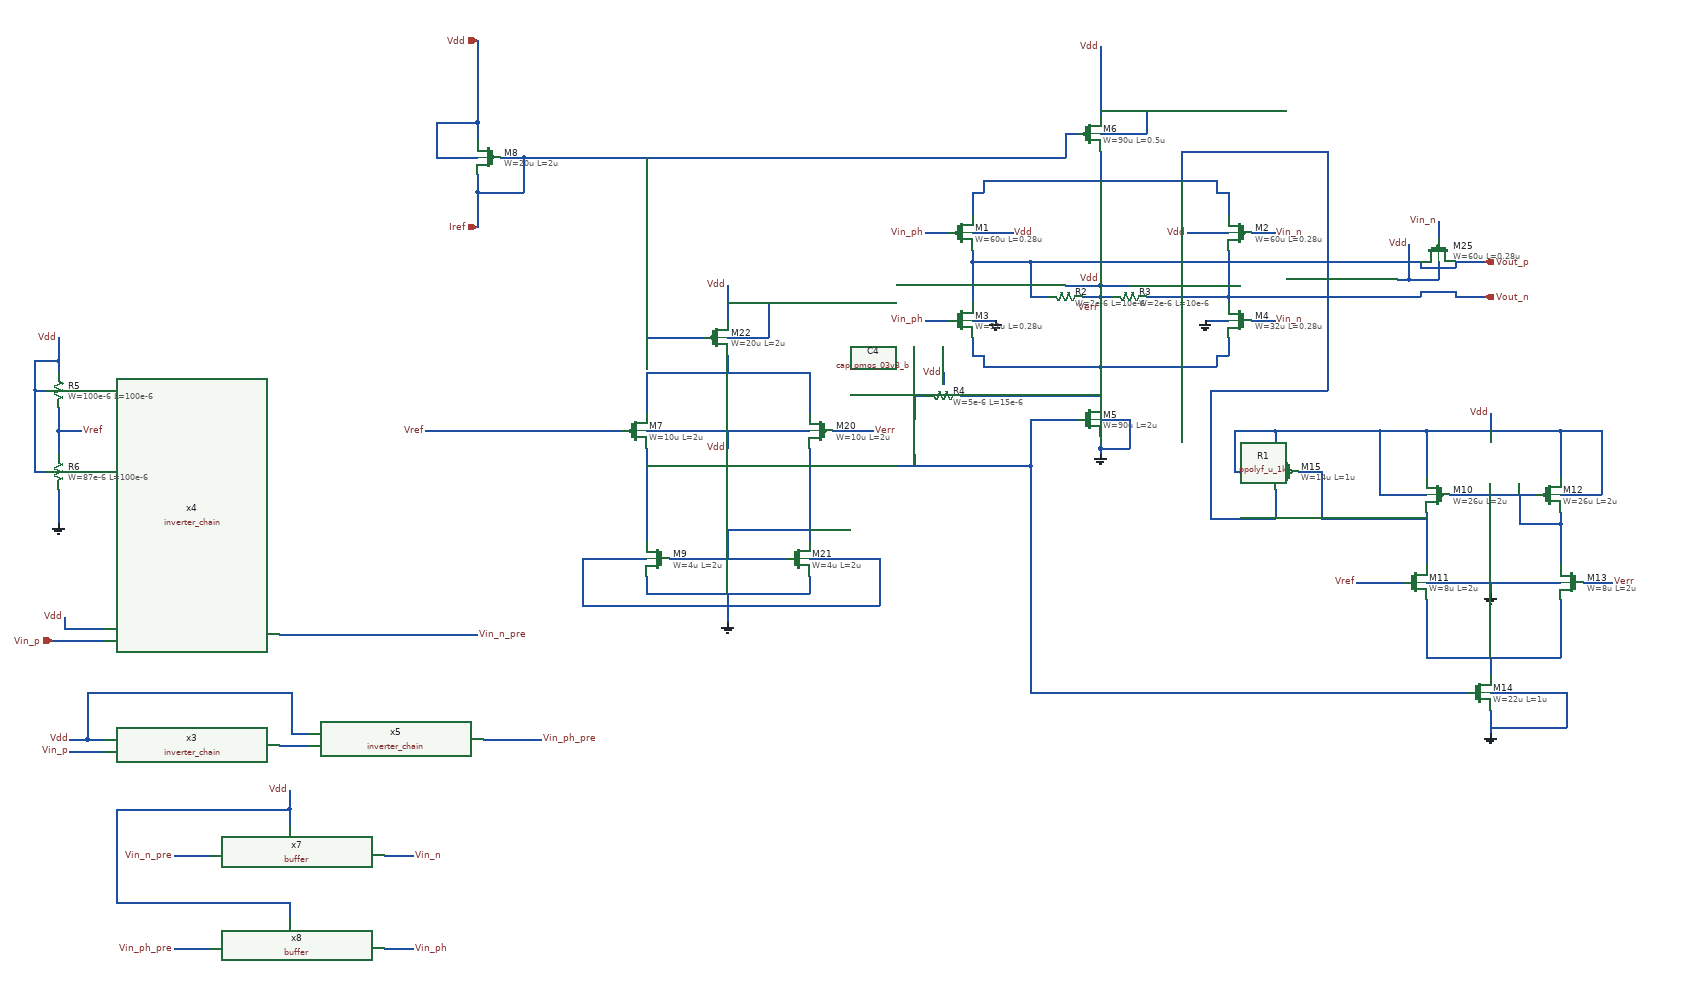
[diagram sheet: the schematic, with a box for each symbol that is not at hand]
v {xschem version=3.4.8RC file_version=1.3}
G {}
K {}
V {}
S {}
F {}
E {}
N 0 -40 0 30 {lab=Vout_p}
N 440 20 440 30 {lab=Vout_n}
N 400 60 440 60 {lab=0}
N 0 60 40 60 {lab=0}
N 370 -90 440 -90 {lab=Vdd}
N 0 -90 70 -90 {lab=Vdd}
N 0 90 0 120 {lab=#net1}
N 440 90 440 120 {lab=#net1}
N 420 120 440 120 {lab=#net1}
N 0 120 20 120 {lab=#net1}
N 20 120 20 140 {lab=#net1}
N 220 140 420 140 {lab=#net1}
N 420 120 420 140 {lab=#net1}
N 0 -160 0 -120 {lab=#net2}
N 0 -160 20 -160 {lab=#net2}
N 20 -180 20 -160 {lab=#net2}
N 440 -160 440 -120 {lab=#net2}
N 420 -160 440 -160 {lab=#net2}
N 420 -180 420 -160 {lab=#net2}
N 60 -180 420 -180 {lab=#net2}
N 220 140 220 200 {lab=#net1}
N 480 -90 520 -90 {lab=Vin_n}
N -80 -90 -40 -90 {lab=Vin_ph}
N -80 60 -40 60 {lab=Vin_ph}
N 480 60 520 60 {lab=Vin_n}
N 220 -410 220 -360 {lab=Vdd}
N 100 -40 770 -40 {lab=Vout_p}
N 440 20 770 20 {lab=Vout_n}
N 220 280 220 290 {lab=0}
N 220 230 270 230 {lab=0}
N 270 230 270 280 {lab=0}
N 220 280 270 280 {lab=0}
N -850 -280 -850 -250 {lab=Vdd}
N -850 -420 -850 -330 {lab=Vdd}
N -850 -160 -850 -100 {lab=Iref}
N -920 -220 -850 -220 {lab=Vdd}
N -920 -280 -920 -220 {lab=Vdd}
N -920 -280 -850 -280 {lab=Vdd}
N -770 -220 -770 -160 {lab=Iref}
N -850 -160 -770 -160 {lab=Iref}
N 220 -360 220 -290 {lab=Vdd}
N 100 -40 100 20 {lab=Vout_p}
N 100 20 130 20 {lab=Vout_p}
N 300 20 440 20 {lab=Vout_n}
N 220 20 240 20 {lab=Verr}
N 220 0 270 0 {lab=Vdd}
N 220 -10 220 0 {lab=Vdd}
N 220 20 220 40 {lab=Verr}
N -810 -220 -770 -220 {lab=Iref}
N -1580 610 -1490 610 {lab=#net3}
N -1560 590 -1490 590 {lab=Vdd}
N -1560 570 -1560 590 {lab=Vdd}
N -1190 600 -850 600 {lab=Vin_n_pre}
N -1520 780 -1490 780 {lab=Vdd}
N -1550 800 -1490 800 {lab=Vin_p}
N -1190 790 -1140 790 {lab=#net4}
N -840 780 -740 780 {lab=Vin_ph_pre}
N -1520 700 -1520 780 {lab=Vdd}
N -1520 700 -1170 700 {lab=Vdd}
N -1170 700 -1170 770 {lab=Vdd}
N -1170 770 -1140 770 {lab=Vdd}
N -1172.5 900 -1172.5 927.5 {lab=Vdd}
N -1010 980 -960 980 {lab=Vin_n}
N -1010 1140 -960 1140 {lab=Vin_ph}
N -1370 980 -1310 980 {lab=Vin_n_pre}
N -1370 1140 -1310 1140 {lab=Vin_ph_pre}
N -1470 900 -1470 1060 {lab=Vdd}
N -1470 900 -1172.5 900 {lab=Vdd}
N -1470 1060 -1172.5 1060 {lab=Vdd}
N -1172.5 1060 -1172.5 1087.5 {lab=Vdd}
N -1570 350 -1570 410 {lab=0}
N -1570 250 -1570 290 {lab=Vref}
N -1570 130 -1570 150 {lab=Vdd}
N -1610 180 -1590 180 {lab=Vdd}
N -1610 180 -1610 320 {lab=Vdd}
N -1610 320 -1590 320 {lab=Vdd}
N -1610 130 -1610 180 {lab=Vdd}
N -1610 130 -1570 130 {lab=Vdd}
N 20 140 220 140 {lab=#net1}
N 0 -60 0 -40 {lab=Vout_p}
N 440 -60 440 20 {lab=Vout_n}
N 220 260 220 280 {lab=0}
N -850 -330 -850 -280 {lab=Vdd}
N -850 -190 -850 -160 {lab=Iref}
N 0 -40 100 -40 {lab=Vout_p}
N 160 0 220 0 {lab=Vdd}
N 190 20 220 20 {lab=Verr}
N 20 -180 60 -180 {lab=#net2}
N -1550 780 -1520 780 {lab=Vdd}
N -1172.5 867.5 -1172.5 900 {lab=Vdd}
N -1570 210 -1570 250 {lab=Vref}
N -1570 90 -1570 130 {lab=Vdd}
N 830 20 880 20 {lab=Vout_n}
N 830 -40 880 -40 {lab=Vout_p}
N 220 -230 220 -180 {lab=#net2}
N 220 -260 300 -260 {lab=Vdd}
N 300 -300 300 -260 {lab=Vdd}
N 220 -300 300 -300 {lab=Vdd}
N -770 -220 160 -220 {lab=Iref}
N 160 -260 160 -220 {lab=Iref}
N 160 -260 180 -260 {lab=Iref}
N -560 280 -560 440 {lab=#net5}
N -280 280 -280 440 {lab=#net6}
N -520 470 -320 470 {lab=#net6}
N -420 420 -420 470 {lab=#net6}
N -420 420 -280 420 {lab=#net6}
N -560 500 -560 530 {lab=0}
N -560 530 -280 530 {lab=0}
N -280 500 -280 530 {lab=0}
N -420 530 -420 580 {lab=0}
N -670 470 -560 470 {lab=0}
N -670 470 -670 550 {lab=0}
N -670 550 -420 550 {lab=0}
N -280 470 -160 470 {lab=0}
N -160 470 -160 550 {lab=0}
N -410 550 -160 550 {lab=0}
N -420 550 -410 550 {lab=0}
N -560 250 -280 250 {lab=Vdd}
N -420 250 -420 280 {lab=Vdd}
N -240 250 -170 250 {lab=Verr}
N -940 250 -600 250 {lab=Vref}
N -560 150 -560 220 {lab=#net7}
N -560 150 -280 150 {lab=#net7}
N -280 150 -280 220 {lab=#net7}
N -420 120 -420 150 {lab=#net7}
N -420 0 -420 60 {lab=Vdd}
N -560 90 -460 90 {lab=Iref}
N -560 -220 -560 90 {lab=Iref}
N -560 310 -520 310 {lab=#net5}
N 140 230 180 230 {lab=#net5}
N -420 90 -350 90 {lab=Vdd}
N -350 30 -350 90 {lab=Vdd}
N -420 30 -350 30 {lab=Vdd}
N -20 190 220 190 {lab=#net1}
N -520 310 100 310 {lab=#net5}
N 100 230 100 310 {lab=#net5}
N 100 230 140 230 {lab=#net5}
N -100 190 -80 190 {lab=#net8}
N -100 190 -100 230 {lab=#net8}
N -100 290 -100 310 {lab=#net5}
N -50 150 -50 170 {lab=Vdd}
N 770 -40 770 -30 {lab=Vout_p}
N 770 -30 830 -30 {lab=Vout_p}
N 830 -40 830 -30 {lab=Vout_p}
N 770 10 770 20 {lab=Vout_n}
N 830 10 830 20 {lab=Vout_n}
N 800 -110 800 -80 {lab=Vin_n}
N 750 -10 800 -10 {lab=Vdd}
N 750 -70 750 -10 {lab=Vdd}
N 770 10 830 10 {lab=Vout_n}
N 800 -40 800 -10 {lab=Vdd}
N 820 360 970 360 {lab=#net9}
N 940 360 940 410 {lab=#net9}
N 940 410 1010 410 {lab=#net9}
N 1010 390 1010 410 {lab=#net9}
N 1010 410 1010 480 {lab=#net9}
N 660 510 740 510 {lab=Vref}
N -1570 250 -1530 250 {lab=Vref}
N 780 390 780 480 {lab=#net10}
N 780 540 780 570 {lab=#net11}
N 1010 540 1010 570 {lab=#net11}
N 780 250 780 330 {lab=Vdd}
N 780 250 1010 250 {lab=Vdd}
N 1010 250 1010 330 {lab=Vdd}
N 890 220 890 250 {lab=Vdd}
N 1010 360 1080 360 {lab=Vdd}
N 1080 250 1080 360 {lab=Vdd}
N 1010 250 1080 250 {lab=Vdd}
N 700 360 780 360 {lab=Vdd}
N 700 250 700 360 {lab=Vdd}
N 700 250 780 250 {lab=Vdd}
N 780 510 1010 510 {lab=0}
N 890 510 890 530 {lab=0}
N 780 570 780 640 {lab=#net11}
N 780 640 1010 640 {lab=#net11}
N 1010 570 1010 640 {lab=#net11}
N 890 640 890 670 {lab=#net11}
N 890 730 890 770 {lab=0}
N 890 700 1020 700 {lab=0}
N 1020 700 1020 760 {lab=0}
N 890 760 1020 760 {lab=0}
N 100 310 100 700 {lab=#net5}
N 100 700 850 700 {lab=#net5}
N 560 320 600 320 {lab=#net10}
N 600 320 600 400 {lab=#net10}
N 600 400 780 400 {lab=#net10}
N 520 250 520 290 {lab=Vdd}
N 520 250 700 250 {lab=Vdd}
N 520 350 520 400 {lab=#net2}
N 410 400 520 400 {lab=#net2}
N 410 180 410 400 {lab=#net2}
N 410 180 610 180 {lab=#net2}
N 610 -230 610 180 {lab=#net2}
N 360 -230 610 -230 {lab=#net2}
N 360 -230 360 -180 {lab=#net2}
N 1050 510 1100 510 {lab=Verr}
N 450 320 520 320 {lab=Vdd}
N 450 250 450 320 {lab=Vdd}
N 450 250 520 250 {lab=Vdd}
N 730 -10 750 -10 {lab=Vdd}
C {gnd.sym} 400 60 1 1 {name=l5 lab=0}
C {gnd.sym} 40 60 3 0 {name=l6 lab=0}
C {lab_wire.sym} 370 -90 0 0 {name=p5 sig_type=std_logic lab=Vdd}
C {lab_wire.sym} 70 -90 0 1 {name=p6 sig_type=std_logic lab=Vdd}
C {lab_wire.sym} 520 60 0 1 {name=p4 sig_type=std_logic lab=Vin_n}
C {lab_wire.sym} 220 -410 0 0 {name=p7 sig_type=std_logic lab=Vdd}
C {lab_wire.sym} 520 -90 0 1 {name=p2 sig_type=std_logic lab=Vin_n}
C {symbols/pfet_03v3.sym} -20 -90 0 0 {name=M1
L=0.28u
W=60u
nf=15
m=1
ad="'int((nf+1)/2) * W/nf * 0.18u'"
pd="'2*int((nf+1)/2) * (W/nf + 0.18u)'"
as="'int((nf+2)/2) * W/nf * 0.18u'"
ps="'2*int((nf+2)/2) * (W/nf + 0.18u)'"
nrd="'0.18u / W'" nrs="'0.18u / W'"
sa=0 sb=0 sd=0
model=pfet_03v3
spiceprefix=X
}
C {symbols/pfet_03v3.sym} 460 -90 0 1 {name=M2
L=0.28u
W=60u
nf=15
m=1
ad="'int((nf+1)/2) * W/nf * 0.18u'"
pd="'2*int((nf+1)/2) * (W/nf + 0.18u)'"
as="'int((nf+2)/2) * W/nf * 0.18u'"
ps="'2*int((nf+2)/2) * (W/nf + 0.18u)'"
nrd="'0.18u / W'" nrs="'0.18u / W'"
sa=0 sb=0 sd=0
model=pfet_03v3
spiceprefix=X
}
C {symbols/nfet_03v3.sym} -20 60 0 0 {name=M3
L=0.28u
W=32u
nf=10
m=1
ad="'int((nf+1)/2) * W/nf * 0.18u'"
pd="'2*int((nf+1)/2) * (W/nf + 0.18u)'"
as="'int((nf+2)/2) * W/nf * 0.18u'"
ps="'2*int((nf+2)/2) * (W/nf + 0.18u)'"
nrd="'0.18u / W'" nrs="'0.18u / W'"
sa=0 sb=0 sd=0
model=nfet_03v3
spiceprefix=X
}
C {symbols/nfet_03v3.sym} 460 60 0 1 {name=M4
L=0.28u
W=32u
nf=10
m=1
ad="'int((nf+1)/2) * W/nf * 0.18u'"
pd="'2*int((nf+1)/2) * (W/nf + 0.18u)'"
as="'int((nf+2)/2) * W/nf * 0.18u'"
ps="'2*int((nf+2)/2) * (W/nf + 0.18u)'"
nrd="'0.18u / W'" nrs="'0.18u / W'"
sa=0 sb=0 sd=0
model=nfet_03v3
spiceprefix=X
}
C {gnd.sym} 220 290 0 0 {name=l4 lab=0}
C {symbols/nfet_03v3.sym} 200 230 0 0 {name=M5
L=2u
W=90u
nf=18
m=1
ad="'int((nf+1)/2) * W/nf * 0.18u'"
pd="'2*int((nf+1)/2) * (W/nf + 0.18u)'"
as="'int((nf+2)/2) * W/nf * 0.18u'"
ps="'2*int((nf+2)/2) * (W/nf + 0.18u)'"
nrd="'0.18u / W'" nrs="'0.18u / W'"
sa=0 sb=0 sd=0
model=nfet_03v3
spiceprefix=X
}
C {symbols/pfet_03v3.sym} 200 -260 0 0 {name=M6
L=0.5u
W=90u
nf=18
m=8
ad="'int((nf+1)/2) * W/nf * 0.18u'"
pd="'2*int((nf+1)/2) * (W/nf + 0.18u)'"
as="'int((nf+2)/2) * W/nf * 0.18u'"
ps="'2*int((nf+2)/2) * (W/nf + 0.18u)'"
nrd="'0.18u / W'" nrs="'0.18u / W'"
sa=0 sb=0 sd=0
model=pfet_03v3
spiceprefix=X
}
C {symbols/pfet_03v3.sym} -830 -220 0 1 {name=M8
L=2u
W=20u
nf=5
m=1
ad="'int((nf+1)/2) * W/nf * 0.18u'"
pd="'2*int((nf+1)/2) * (W/nf + 0.18u)'"
as="'int((nf+2)/2) * W/nf * 0.18u'"
ps="'2*int((nf+2)/2) * (W/nf + 0.18u)'"
nrd="'0.18u / W'" nrs="'0.18u / W'"
sa=0 sb=0 sd=0
model=pfet_03v3
spiceprefix=X
}
C {symbols/ppolyf_u_1k.sym} 160 20 1 0 {name=R2
W=2e-6
L=10e-6
model=ppolyf_u_1k
spiceprefix=X
m=1}
C {symbols/ppolyf_u_1k.sym} 270 20 1 0 {name=R3
W=2e-6
L=10e-6
model=ppolyf_u_1k
spiceprefix=X
m=1}
C {lab_wire.sym} 220 -10 0 0 {name=p33 sig_type=std_logic lab=Vdd}
C {lab_wire.sym} 220 40 3 0 {name=p34 sig_type=std_logic lab=Verr}
C {lab_wire.sym} -850 600 0 1 {name=p39 sig_type=std_logic lab=Vin_n_pre}
C {inverter_chain.sym} -1340 600 0 0 {name=x4}
C {lab_wire.sym} -1560 570 0 0 {name=p38 sig_type=std_logic lab=Vdd}
C {lab_wire.sym} -80 -90 0 0 {name=p1 sig_type=std_logic lab=Vin_ph}
C {lab_wire.sym} -80 60 0 0 {name=p3 sig_type=std_logic lab=Vin_ph}
C {lab_wire.sym} -740 780 0 1 {name=p49 sig_type=std_logic lab=Vin_ph_pre}
C {inverter_chain.sym} -1340 790 0 0 {name=x3}
C {lab_wire.sym} -1550 780 0 0 {name=p16 sig_type=std_logic lab=Vdd}
C {lab_wire.sym} -1550 800 0 0 {name=p17 sig_type=std_logic lab=Vin_p}
C {inverter_chain.sym} -990 780 0 0 {name=x5}
C {buffer.sym} -1160 980 0 0 {name=x7}
C {buffer.sym} -1160 1140 0 0 {name=x8}
C {lab_wire.sym} -960 980 0 1 {name=p18 sig_type=std_logic lab=Vin_n}
C {lab_wire.sym} -960 1140 0 1 {name=p22 sig_type=std_logic lab=Vin_ph}
C {lab_wire.sym} -1370 980 0 0 {name=p30 sig_type=std_logic lab=Vin_n_pre}
C {lab_wire.sym} -1370 1140 0 0 {name=p31 sig_type=std_logic lab=Vin_ph_pre}
C {lab_wire.sym} -1172.5 867.5 0 0 {name=p40 sig_type=std_logic lab=Vdd}
C {symbols/ppolyf_u_1k.sym} -1570 180 0 0 {name=R5
W=100e-6
L=100e-6
model=ppolyf_u_1k
spiceprefix=X
m=1}
C {symbols/ppolyf_u_1k.sym} -1570 320 0 0 {name=R6
W=87e-6
L=100e-6
model=ppolyf_u_1k
spiceprefix=X
m=2}
C {gnd.sym} -1570 410 0 0 {name=l15 lab=0}
C {lab_wire.sym} -1570 90 0 0 {name=p25 sig_type=std_logic lab=Vdd}
C {symbols/pfet_03v3.sym} -580 250 0 0 {name=M7
L=2u
W=10u
nf=2
m=1
ad="'int((nf+1)/2) * W/nf * 0.18u'"
pd="'2*int((nf+1)/2) * (W/nf + 0.18u)'"
as="'int((nf+2)/2) * W/nf * 0.18u'"
ps="'2*int((nf+2)/2) * (W/nf + 0.18u)'"
nrd="'0.18u / W'" nrs="'0.18u / W'"
sa=0 sb=0 sd=0
model=pfet_03v3
spiceprefix=X
}
C {symbols/nfet_03v3.sym} -540 470 0 1 {name=M9
L=2u
W=4u
nf=1
m=1
ad="'int((nf+1)/2) * W/nf * 0.18u'"
pd="'2*int((nf+1)/2) * (W/nf + 0.18u)'"
as="'int((nf+2)/2) * W/nf * 0.18u'"
ps="'2*int((nf+2)/2) * (W/nf + 0.18u)'"
nrd="'0.18u / W'" nrs="'0.18u / W'"
sa=0 sb=0 sd=0
model=nfet_03v3
spiceprefix=X
}
C {symbols/pfet_03v3.sym} -260 250 0 1 {name=M20
L=2u
W=10u
nf=2
m=1
ad="'int((nf+1)/2) * W/nf * 0.18u'"
pd="'2*int((nf+1)/2) * (W/nf + 0.18u)'"
as="'int((nf+2)/2) * W/nf * 0.18u'"
ps="'2*int((nf+2)/2) * (W/nf + 0.18u)'"
nrd="'0.18u / W'" nrs="'0.18u / W'"
sa=0 sb=0 sd=0
model=pfet_03v3
spiceprefix=X
}
C {symbols/nfet_03v3.sym} -300 470 0 0 {name=M21
L=2u
W=4u
nf=1
m=1
ad="'int((nf+1)/2) * W/nf * 0.18u'"
pd="'2*int((nf+1)/2) * (W/nf + 0.18u)'"
as="'int((nf+2)/2) * W/nf * 0.18u'"
ps="'2*int((nf+2)/2) * (W/nf + 0.18u)'"
nrd="'0.18u / W'" nrs="'0.18u / W'"
sa=0 sb=0 sd=0
model=nfet_03v3
spiceprefix=X
}
C {gnd.sym} -420 580 0 0 {name=l3 lab=0}
C {lab_wire.sym} -420 280 0 0 {name=p8 sig_type=std_logic lab=Vdd}
C {lab_wire.sym} -170 250 0 1 {name=p32 sig_type=std_logic lab=Verr}
C {symbols/pfet_03v3.sym} -440 90 0 0 {name=M22
L=2u
W=20u
nf=5
m=1
ad="'int((nf+1)/2) * W/nf * 0.18u'"
pd="'2*int((nf+1)/2) * (W/nf + 0.18u)'"
as="'int((nf+2)/2) * W/nf * 0.18u'"
ps="'2*int((nf+2)/2) * (W/nf + 0.18u)'"
nrd="'0.18u / W'" nrs="'0.18u / W'"
sa=0 sb=0 sd=0
model=pfet_03v3
spiceprefix=X
}
C {lab_wire.sym} -420 0 0 0 {name=p35 sig_type=std_logic lab=Vdd}
C {symbols/cap_pmos_03v3_b.sym} -100 260 2 0 {name=C4
W=10e-6
L=10e-6
model=cap_pmos_03v3_b
spiceprefix=X
m=1}
C {symbols/ppolyf_u_1k.sym} -50 190 1 0 {name=R4
W=5e-6
L=15e-6
model=ppolyf_u_1k
spiceprefix=X
m=1}
C {lab_wire.sym} -50 150 0 0 {name=p36 sig_type=std_logic lab=Vdd}
C {symbols/pfet_03v3.sym} 800 -60 1 0 {name=M25
L=0.28u
W=60u
nf=10
m=1
ad="'int((nf+1)/2) * W/nf * 0.18u'"
pd="'2*int((nf+1)/2) * (W/nf + 0.18u)'"
as="'int((nf+2)/2) * W/nf * 0.18u'"
ps="'2*int((nf+2)/2) * (W/nf + 0.18u)'"
nrd="'0.18u / W'" nrs="'0.18u / W'"
sa=0 sb=0 sd=0
model=pfet_03v3
spiceprefix=X
}
C {lab_wire.sym} 800 -110 0 0 {name=p48 sig_type=std_logic lab=Vin_n}
C {lab_wire.sym} 750 -70 0 0 {name=p51 sig_type=std_logic lab=Vdd}
C {symbols/pfet_03v3.sym} 800 360 0 1 {name=M10
L=2u
W=26u
nf=10
m=1
ad="'int((nf+1)/2) * W/nf * 0.18u'"
pd="'2*int((nf+1)/2) * (W/nf + 0.18u)'"
as="'int((nf+2)/2) * W/nf * 0.18u'"
ps="'2*int((nf+2)/2) * (W/nf + 0.18u)'"
nrd="'0.18u / W'" nrs="'0.18u / W'"
sa=0 sb=0 sd=0
model=pfet_03v3
spiceprefix=X
}
C {symbols/nfet_03v3.sym} 760 510 0 0 {name=M11
L=2u
W=8u
nf=1
m=1
ad="'int((nf+1)/2) * W/nf * 0.18u'"
pd="'2*int((nf+1)/2) * (W/nf + 0.18u)'"
as="'int((nf+2)/2) * W/nf * 0.18u'"
ps="'2*int((nf+2)/2) * (W/nf + 0.18u)'"
nrd="'0.18u / W'" nrs="'0.18u / W'"
sa=0 sb=0 sd=0
model=nfet_03v3
spiceprefix=X
}
C {symbols/pfet_03v3.sym} 990 360 0 0 {name=M12
L=2u
W=26u
nf=10
m=1
ad="'int((nf+1)/2) * W/nf * 0.18u'"
pd="'2*int((nf+1)/2) * (W/nf + 0.18u)'"
as="'int((nf+2)/2) * W/nf * 0.18u'"
ps="'2*int((nf+2)/2) * (W/nf + 0.18u)'"
nrd="'0.18u / W'" nrs="'0.18u / W'"
sa=0 sb=0 sd=0
model=pfet_03v3
spiceprefix=X
}
C {symbols/nfet_03v3.sym} 1030 510 0 1 {name=M13
L=2u
W=8u
nf=1
m=1
ad="'int((nf+1)/2) * W/nf * 0.18u'"
pd="'2*int((nf+1)/2) * (W/nf + 0.18u)'"
as="'int((nf+2)/2) * W/nf * 0.18u'"
ps="'2*int((nf+2)/2) * (W/nf + 0.18u)'"
nrd="'0.18u / W'" nrs="'0.18u / W'"
sa=0 sb=0 sd=0
model=nfet_03v3
spiceprefix=X
}
C {lab_wire.sym} -1530 250 0 1 {name=p14 sig_type=std_logic lab=Vref}
C {lab_wire.sym} -940 250 0 0 {name=p19 sig_type=std_logic lab=Vref}
C {lab_wire.sym} 660 510 0 0 {name=p26 sig_type=std_logic lab=Vref}
C {lab_wire.sym} 890 220 0 0 {name=p27 sig_type=std_logic lab=Vdd}
C {gnd.sym} 890 530 0 0 {name=l1 lab=0}
C {symbols/nfet_03v3.sym} 870 700 0 0 {name=M14
L=1u
W=22u
nf=11
m=1
ad="'int((nf+1)/2) * W/nf * 0.18u'"
pd="'2*int((nf+1)/2) * (W/nf + 0.18u)'"
as="'int((nf+2)/2) * W/nf * 0.18u'"
ps="'2*int((nf+2)/2) * (W/nf + 0.18u)'"
nrd="'0.18u / W'" nrs="'0.18u / W'"
sa=0 sb=0 sd=0
model=nfet_03v3
spiceprefix=X
}
C {gnd.sym} 890 770 0 0 {name=l7 lab=0}
C {symbols/pfet_03v3.sym} 540 320 0 1 {name=M15
L=1u
W=14u
nf=1
m=1
ad="'int((nf+1)/2) * W/nf * 0.18u'"
pd="'2*int((nf+1)/2) * (W/nf + 0.18u)'"
as="'int((nf+2)/2) * W/nf * 0.18u'"
ps="'2*int((nf+2)/2) * (W/nf + 0.18u)'"
nrd="'0.18u / W'" nrs="'0.18u / W'"
sa=0 sb=0 sd=0
model=pfet_03v3
spiceprefix=X
}
C {lab_wire.sym} 1100 510 0 1 {name=p28 sig_type=std_logic lab=Verr}
C {ipin.sym} -850 -100 3 0 {name=p12 lab=Iref}
C {ipin.sym} -850 -420 1 0 {name=p13 lab=Vdd}
C {opin.sym} 880 -40 0 0 {name=p10 lab=Vout_p}
C {opin.sym} 880 20 0 0 {name=p11 lab=Vout_n}
C {symbols/ppolyf_u_1k.sym} 710 -10 2 0 {name=R1
W=30e-6
L=3e-6
model=ppolyf_u_1k
spiceprefix=X
m=1}
C {ipin.sym} -1580 610 0 0 {name=p9 lab=Vin_p}
